VERSION 5.7 ;
  NOWIREEXTENSIONATPIN ON ;
  DIVIDERCHAR "/" ;
  BUSBITCHARS "[]" ;
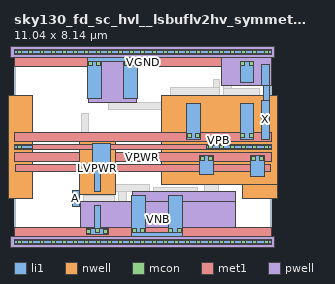
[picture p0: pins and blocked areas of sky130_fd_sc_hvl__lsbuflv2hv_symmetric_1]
MACRO sky130_fd_sc_hvl__lsbuflv2hv_symmetric_1
  CLASS BLOCK ;
  FOREIGN sky130_fd_sc_hvl__lsbuflv2hv_symmetric_1 ;
  ORIGIN 0.000 0.000 ;
  SIZE 11.040 BY 8.140 ;
  PIN A
    ANTENNAGATEAREA 0.252000 ;
    PORT
      LAYER li1 ;
        RECT 2.495 1.530 2.805 2.200 ;
    END
  END A
  PIN LVPWR
    ANTENNADIFFAREA 0.982800 ;
    PORT
      LAYER nwell ;
        RECT 2.800 2.015 4.335 4.325 ;
      LAYER li1 ;
        RECT 3.345 3.225 4.115 4.200 ;
        RECT 3.435 3.075 4.115 3.225 ;
        RECT 3.435 2.165 3.705 3.075 ;
      LAYER mcon ;
        RECT 3.485 3.050 3.655 3.220 ;
        RECT 3.845 3.105 4.015 3.275 ;
      LAYER met1 ;
        RECT 0.070 3.020 10.970 3.305 ;
    END
  END LVPWR
  PIN VGND
    USE GROUND ;
    PORT
      LAYER li1 ;
        RECT 3.145 7.715 5.295 7.885 ;
        RECT 3.145 6.165 3.735 7.715 ;
        RECT 4.705 6.165 5.295 7.715 ;
        RECT 9.690 6.835 10.280 7.745 ;
      LAYER mcon ;
        RECT 3.175 7.545 3.345 7.715 ;
        RECT 3.535 7.545 3.705 7.715 ;
        RECT 4.735 7.545 4.905 7.715 ;
        RECT 5.095 7.545 5.265 7.715 ;
        RECT 9.720 7.545 9.890 7.715 ;
        RECT 10.080 7.545 10.250 7.715 ;
      LAYER met1 ;
        RECT 0.000 7.515 11.040 7.885 ;
    END
    PORT
      LAYER li1 ;
        RECT 3.435 0.565 3.705 1.575 ;
        RECT 3.095 0.335 4.045 0.565 ;
        RECT 5.050 0.425 5.640 1.975 ;
        RECT 6.610 0.425 7.200 1.975 ;
        RECT 5.050 0.255 7.200 0.425 ;
      LAYER mcon ;
        RECT 3.125 0.365 3.295 0.535 ;
        RECT 3.485 0.425 3.655 0.595 ;
        RECT 3.845 0.365 4.015 0.535 ;
        RECT 5.080 0.425 5.250 0.595 ;
        RECT 5.440 0.425 5.610 0.595 ;
        RECT 6.640 0.425 6.810 0.595 ;
        RECT 7.000 0.425 7.170 0.595 ;
      LAYER met1 ;
        RECT 0.000 0.255 11.040 0.625 ;
    END
  END VGND
  PIN VNB
    ANTENNADIFFAREA 1.876800 ;
    PORT
      LAYER pwell ;
        RECT -0.130 7.925 11.170 8.355 ;
        RECT 3.185 5.975 5.255 7.925 ;
        RECT 8.905 6.725 11.020 7.925 ;
      LAYER li1 ;
        RECT 0.000 8.055 11.040 8.225 ;
      LAYER mcon ;
        RECT 0.155 8.055 0.325 8.225 ;
        RECT 0.635 8.055 0.805 8.225 ;
        RECT 1.115 8.055 1.285 8.225 ;
        RECT 1.595 8.055 1.765 8.225 ;
        RECT 2.075 8.055 2.245 8.225 ;
        RECT 2.555 8.055 2.725 8.225 ;
        RECT 3.035 8.055 3.205 8.225 ;
        RECT 3.515 8.055 3.685 8.225 ;
        RECT 3.995 8.055 4.165 8.225 ;
        RECT 4.475 8.055 4.645 8.225 ;
        RECT 4.955 8.055 5.125 8.225 ;
        RECT 5.435 8.055 5.605 8.225 ;
        RECT 5.915 8.055 6.085 8.225 ;
        RECT 6.395 8.055 6.565 8.225 ;
        RECT 6.875 8.055 7.045 8.225 ;
        RECT 7.355 8.055 7.525 8.225 ;
        RECT 7.835 8.055 8.005 8.225 ;
        RECT 8.315 8.055 8.485 8.225 ;
        RECT 8.795 8.055 8.965 8.225 ;
        RECT 9.275 8.055 9.445 8.225 ;
        RECT 9.755 8.055 9.925 8.225 ;
        RECT 10.235 8.055 10.405 8.225 ;
        RECT 10.715 8.055 10.885 8.225 ;
      LAYER met1 ;
        RECT 0.000 8.025 11.040 8.255 ;
    END
    PORT
      LAYER pwell ;
        RECT 5.090 1.725 9.500 2.165 ;
        RECT 2.855 0.215 9.500 1.725 ;
        RECT -0.130 -0.215 11.170 0.215 ;
      LAYER li1 ;
        RECT 0.000 -0.085 11.040 0.085 ;
      LAYER mcon ;
        RECT 0.155 -0.085 0.325 0.085 ;
        RECT 0.635 -0.085 0.805 0.085 ;
        RECT 1.115 -0.085 1.285 0.085 ;
        RECT 1.595 -0.085 1.765 0.085 ;
        RECT 2.075 -0.085 2.245 0.085 ;
        RECT 2.555 -0.085 2.725 0.085 ;
        RECT 3.035 -0.085 3.205 0.085 ;
        RECT 3.515 -0.085 3.685 0.085 ;
        RECT 3.995 -0.085 4.165 0.085 ;
        RECT 4.475 -0.085 4.645 0.085 ;
        RECT 4.955 -0.085 5.125 0.085 ;
        RECT 5.435 -0.085 5.605 0.085 ;
        RECT 5.915 -0.085 6.085 0.085 ;
        RECT 6.395 -0.085 6.565 0.085 ;
        RECT 6.875 -0.085 7.045 0.085 ;
        RECT 7.355 -0.085 7.525 0.085 ;
        RECT 7.835 -0.085 8.005 0.085 ;
        RECT 8.315 -0.085 8.485 0.085 ;
        RECT 8.795 -0.085 8.965 0.085 ;
        RECT 9.275 -0.085 9.445 0.085 ;
        RECT 9.755 -0.085 9.925 0.085 ;
        RECT 10.235 -0.085 10.405 0.085 ;
        RECT 10.715 -0.085 10.885 0.085 ;
      LAYER met1 ;
        RECT 0.000 -0.115 11.040 0.115 ;
    END
  END VNB
  PIN VPB
    ANTENNADIFFAREA 0.340000 ;
    PORT
      LAYER nwell ;
        RECT -0.330 1.885 0.800 6.255 ;
        RECT 6.335 2.465 11.370 6.255 ;
        RECT 9.800 1.885 11.370 2.465 ;
      LAYER li1 ;
        RECT 0.000 3.985 0.800 4.155 ;
        RECT 8.235 3.985 11.040 4.155 ;
      LAYER mcon ;
        RECT 0.155 3.985 0.325 4.155 ;
        RECT 8.315 3.985 8.485 4.155 ;
        RECT 8.795 3.985 8.965 4.155 ;
        RECT 9.275 3.985 9.445 4.155 ;
        RECT 9.755 3.985 9.925 4.155 ;
        RECT 10.235 3.985 10.405 4.155 ;
        RECT 10.715 3.985 10.885 4.155 ;
      LAYER met1 ;
        RECT 0.000 3.955 11.040 4.185 ;
    END
  END VPB
  PIN VPWR
    USE POWER ;
    PORT
      LAYER li1 ;
        RECT 7.955 2.875 8.545 3.705 ;
        RECT 10.125 2.795 10.715 3.705 ;
      LAYER mcon ;
        RECT 7.985 3.475 8.155 3.645 ;
        RECT 8.345 3.475 8.515 3.645 ;
        RECT 10.155 3.475 10.325 3.645 ;
        RECT 10.515 3.475 10.685 3.645 ;
      LAYER met1 ;
        RECT 0.000 3.445 11.040 3.815 ;
    END
    PORT
      LAYER li1 ;
        RECT 7.390 4.405 7.980 5.945 ;
        RECT 9.690 4.405 10.280 5.945 ;
      LAYER mcon ;
        RECT 7.420 4.495 7.590 4.665 ;
        RECT 7.780 4.495 7.950 4.665 ;
        RECT 9.720 4.495 9.890 4.665 ;
        RECT 10.080 4.495 10.250 4.665 ;
      LAYER met1 ;
        RECT 0.000 4.325 11.040 4.695 ;
    END
  END VPWR
  PIN X
    ANTENNADIFFAREA 0.596250 ;
    PORT
      LAYER li1 ;
        RECT 10.600 6.725 10.930 7.625 ;
        RECT 10.690 6.055 10.930 6.725 ;
        RECT 10.600 4.405 10.930 6.055 ;
    END
  END X
  OBS
      LAYER li1 ;
        RECT 4.055 5.995 4.385 7.545 ;
        RECT 8.535 6.615 8.815 6.955 ;
        RECT 6.695 6.285 8.815 6.615 ;
        RECT 8.995 6.555 9.325 7.625 ;
        RECT 6.695 5.995 7.025 6.285 ;
        RECT 4.055 5.665 7.025 5.995 ;
        RECT 2.885 3.055 3.175 5.495 ;
        RECT 6.695 4.735 7.025 5.665 ;
        RECT 6.565 4.405 7.025 4.735 ;
        RECT 8.300 4.405 8.630 6.285 ;
        RECT 8.995 6.225 10.520 6.555 ;
        RECT 8.995 4.405 9.325 6.225 ;
        RECT 2.885 2.765 3.265 3.055 ;
        RECT 2.975 1.995 3.265 2.765 ;
        RECT 3.875 2.475 4.185 2.905 ;
        RECT 6.565 2.795 6.895 4.405 ;
        RECT 7.095 2.705 7.765 4.215 ;
        RECT 8.915 2.705 9.835 3.465 ;
        RECT 7.095 2.495 9.835 2.705 ;
        RECT 3.875 2.165 5.790 2.475 ;
        RECT 4.480 2.145 5.790 2.165 ;
        RECT 5.960 2.145 7.850 2.325 ;
        RECT 2.975 1.745 4.310 1.995 ;
        RECT 2.975 0.735 3.265 1.745 ;
        RECT 4.480 1.575 4.810 2.145 ;
        RECT 3.875 1.245 4.810 1.575 ;
        RECT 3.875 0.735 4.185 1.245 ;
        RECT 5.960 0.595 6.290 2.145 ;
        RECT 7.520 0.425 7.850 2.145 ;
        RECT 8.170 0.595 8.760 2.495 ;
        RECT 9.080 0.425 9.410 2.055 ;
        RECT 7.520 0.255 9.410 0.425 ;
  END
END sky130_fd_sc_hvl__lsbuflv2hv_symmetric_1
END LIBRARY

